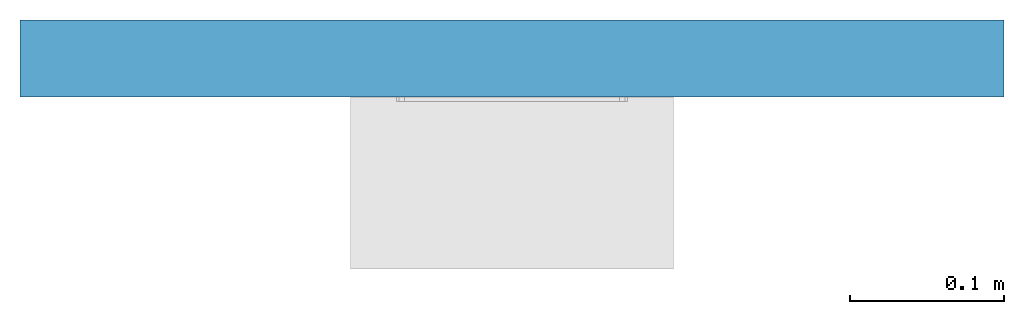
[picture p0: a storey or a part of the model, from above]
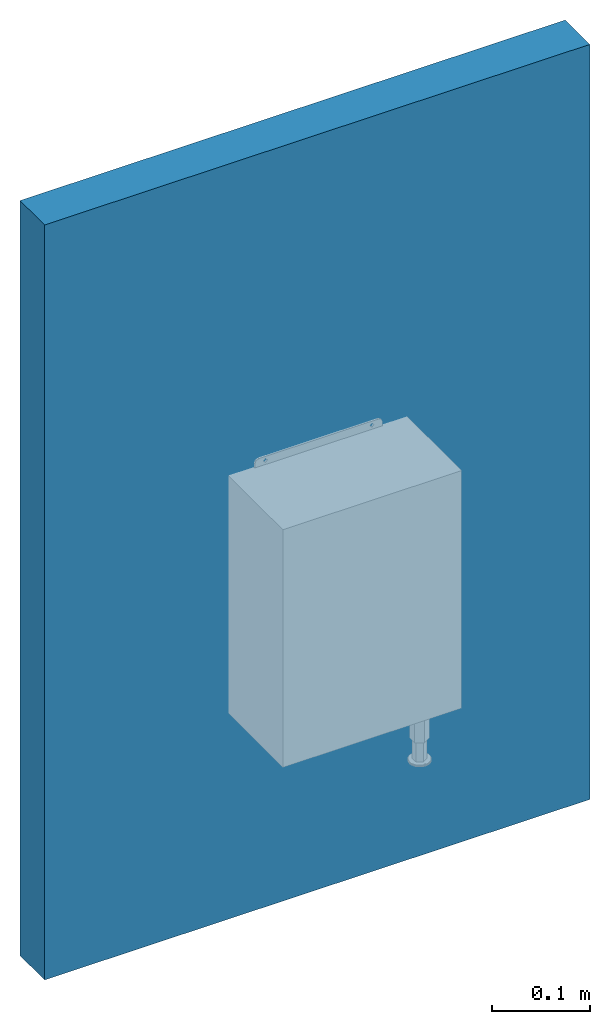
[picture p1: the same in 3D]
Properties of the parts of a building model (IFC2X3)

# File
Description: ViewDefinition [CoordinationView]
Time: 2018-02-23T12:53:45
Written by: The EXPRESS Data Manager Version 5.01.0100.02.64mod : 6 Jun 2012
Made in: 20140709_2115(x64) - Exporter 2014.0.2014.0709 - Default UI
Comment: STEP Physical File produced by: The EXPRESS Data Manager Version 5.01.0100.02.64mod : 6 Jun 2012 * Module: EDMstepFileFactory/EDMstandAlone * Creation date: Fri Feb 23 12:53:45 2018 * Host: BIM-HP * Database: C:\Users\dcole\AppData\Local\Temp\{708D1324-CABC-4FC1-8E1A-0CB21F14B6C8}\ifc * Database version: 5507 * Database creation date: Fri Feb 23 12:53:43 2018 * Schema: IFC2X3 * Model: DataRepository.ifc * Model creation date: Fri Feb 23 12:53:43 2018 * Header model: DataRepository.ifc_HeaderModel * Header model creation date: Fri Feb 23 12:53:43 2018 * EDMuser: sdai-user * EDMgroup: sdai-group * License ID and type: 5605 : Permanent license. Expiry date: * EDMstepFileFactory options: 020000

# IfcProject
LongName: P:\Fastrack\53721_DOLPHIN SOLUTIONS LIMITED\ADDITIONAL DRAWINGS 2018 BIM\IFC\06-3106.ifc

# IfcSite, Default
RefLatitude: 42, 24, 53, 508911; RefLongitude: -71, -15, -29, -58837; RefElevation: 0 mm

# IfcBuilding
Pset_BuildingCommon - NumberOfStoreys: 1

# IfcBuildingStorey, Level 1
LongName: Level 1; Elevation: 0 mm
Constraints - Elevation Base: Project Base Point; Elevation: 0 mm
Identity Data - Name: Level 1; Building Story: yes; Structural: no
Dimensions - Computation Height: 0 mm
Graphics - Color: 0; Symbol at End 1 Default: no; Line Pattern: -3000010; Symbol at End 2 Default: yes; Line Weight: 1

# IfcBuildingElementProxy: 06.3106 Dolphin Behind Mirror Soap Dispenser, 06-3106:06.3106 Dolphin Behind Mirror Soap Dispenser:77520
In: Level 1
Material: Chrome, Stainless Steel
Phasing - Phase Created: New Construction
Dimensions - Volume: 0.00696101 m3; Width: 210mm; Height: 295mm; Weight: Approximate unloaded unit weight: 2kg; Projection: 112mm
Constraints - Offset: 256.377 mm; Level: Level: Level 1; Moves With Nearby Elements: no; Host: Level : Level 1
Pset_ManufacturerTypeInformation - Manufacturer: Dolphin Solutions Ltd.
Pset_BuildingElementProxyCommon - Reference: 06.3106 Dolphin Behind Mirror Soap Dispenser
Identity Data - Address: Southpoint, Compass Park, Bodiam, Robertsbridge, TN32 5BS; Email: info@dolphinsolutions.co.uk; Assembly Code: D2010900; Assembly Description: Other Plumbing Fixtures; Manufacturer: Dolphin Solutions Ltd.; Tel No.: +44 (0) 1424 202 224; Model: 06.3106; Description: Behind mirror soap dispenser; Fax No.: +44 (0) 1424 205 200; URL: www.dolphinsolutions.co.uk
General - Product Page Link: https://www.dolphinsolutions.co.uk/product/dolphin-behind-mirror-soap-dispenser; Warranty: 12 months from date of purchase.; Product Data: Behind mirror, drop-down loading, satin finish stainless steel soap dispenser with 1 litre capacity and chrome soap valve. Usage: Medium Traffic Area.; Liquid Soap: It is recommended usind Dolphin Solutions Ltd. 'Pearlised' liquid soap (Product code 06.8305). It is not recommended using high viscosity liquid soaps or gels, which may impair function. Warning: Liquid soap with high sodium chloride can cause corrosion and may invalidate the product warranty.; Care and Maintenance: If dispenser fails to function, empty the liquid soap from the soap tank and re-fill with warm water. Pump the warm water through the dispenser to dilodge any dried soap residue and then re-fill the container with fresh liquid soap. Use a stainless steel cleaner for brushed stainless steel surfaces. Clean along the grain. Never use an abrasive cloth to remove stubborn stains. Dry with a clean cloth.
Materials and Finishes - Material: Satin finish stainless steel grade 1.4301 (304). Soap Valve: Polished chrome plated brass

# IfcWallStandardCase: Basic Wall:Wall 1, Basic Wall:Wall 1:3092
In: Level 1
Type - PredefinedType: STANDARD; Material: Default Wall 50 mm
Type - Construction - Wrapping at Inserts: Do not wrap; Width: 50 mm; Function: Exterior
Type - Graphics - Coarse Scale Fill Color: 8454143
Type - Analytical Properties - Roughness: 1; Absorptance: 0.1
Structural - Structural: no; Structural Usage: Non-bearing; Enable Analytical Model: no
Constraints - Top Offset: 0 mm; Base is Attached: no; Related to Mass: no; Unconnected Height: 936.967 mm; Location Line: Finish Face: Interior; Base Offset: 0 mm; Top is Attached: no; Top Extension Distance: 0 mm; Base Constraint: Level: Level 1; Base Extension Distance: 0 mm; Room Bounding: yes
Dimensions - Area: 0.599659 m2; Length: 640 mm; Volume: 0.0299829 m3
Phasing - Phase Created: New Construction
Pset_WallCommon - Reference: Wall 1; LoadBearing: no; ExtendToStructure: no; IsExternal: yes
